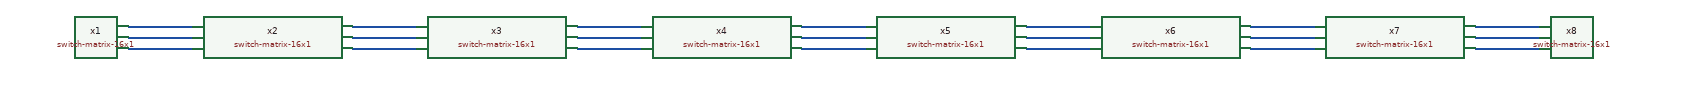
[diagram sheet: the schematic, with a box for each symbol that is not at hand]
v {xschem version=3.4.7 file_version=1.2}
G {}
K {}
V {}
S {}
E {}
N 620 -350 740 -350 {lab=#net1}
N 620 -330 740 -330 {lab=#net2}
N 620 -310 740 -310 {lab=#net3}
N 1040 -350 1160 -350 {lab=#net4}
N 1040 -330 1160 -330 {lab=#net5}
N 1040 -310 1160 -310 {lab=#net6}
N 1460 -350 1580 -350 {lab=#net7}
N 1460 -330 1580 -330 {lab=#net8}
N 1460 -310 1580 -310 {lab=#net9}
N 1880 -350 2000 -350 {lab=#net10}
N 1880 -330 2000 -330 {lab=#net11}
N 1880 -310 2000 -310 {lab=#net12}
N 2300 -350 2420 -350 {lab=#net13}
N 2300 -330 2420 -330 {lab=#net14}
N 2300 -310 2420 -310 {lab=#net15}
N 2720 -350 2840 -350 {lab=#net16}
N 2720 -330 2840 -330 {lab=#net17}
N 2720 -310 2840 -310 {lab=#net18}
N 3140 -350 3260 -350 {lab=#net19}
N 3140 -330 3260 -330 {lab=#net20}
N 3140 -310 3260 -310 {lab=#net21}
C {libs/switch-matrix/switch-matrix-16x1/switch-matrix-16x1.sym} 470 -290 0 0 {name=x1}
C {libs/switch-matrix/switch-matrix-16x1/switch-matrix-16x1.sym} 890 -290 0 0 {name=x2}
C {libs/switch-matrix/switch-matrix-16x1/switch-matrix-16x1.sym} 1310 -290 0 0 {name=x3}
C {libs/switch-matrix/switch-matrix-16x1/switch-matrix-16x1.sym} 1730 -290 0 0 {name=x4}
C {libs/switch-matrix/switch-matrix-16x1/switch-matrix-16x1.sym} 2150 -290 0 0 {name=x5}
C {libs/switch-matrix/switch-matrix-16x1/switch-matrix-16x1.sym} 2570 -290 0 0 {name=x6}
C {libs/switch-matrix/switch-matrix-16x1/switch-matrix-16x1.sym} 2990 -290 0 0 {name=x7}
C {libs/switch-matrix/switch-matrix-16x1/switch-matrix-16x1.sym} 3410 -290 0 0 {name=x8}
